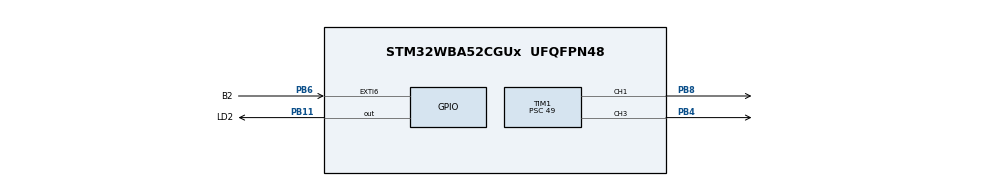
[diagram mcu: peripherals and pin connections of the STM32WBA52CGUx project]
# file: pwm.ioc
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CORTEX_M33_NS.userName=CORTEX_M33
Mcu.Family=STM32WBA
Mcu.Name=STM32WBA52CGUx
Mcu.Package=UFQFPN48
NVIC.EXTI6_IRQn=true\:0\:0\:false\:false\:true\:true\:true\:true
NVIC.PriorityGroup=NVIC_PRIORITYGROUP_4
OSC_IN.GPIO_Label=RCC_OSC_IN
OSC_IN.Mode=HSE-External-Oscillator
OSC_IN.Signal=RCC_OSC_IN
OSC_OUT.GPIO_Label=RCC_OSC_OUT
OSC_OUT.Mode=HSE-External-Oscillator
OSC_OUT.Signal=RCC_OSC_OUT
PA13\ (JTMS/SWDIO).GPIO_Label=DEBUG_JTMS-SWDIO
PA13\ (JTMS/SWDIO).Signal=DEBUG_JTMS-SWDIO
PA14\ (JTCK/SWCLK).GPIO_Label=DEBUG_JTCK-SWCLK
PA14\ (JTCK/SWCLK).Signal=DEBUG_JTCK-SWCLK
PA8.GPIO_Label=USART1_RX
PA8.Signal=USART1_RX
PB11.GPIO_Label=LD2
PB11.GPIO_Speed=GPIO_SPEED_FREQ_HIGH
PB11.Signal=GPIO_Output
PB12.GPIO_Label=USART1_TX
PB12.Signal=USART1_TX
PB4\ (NJTRST).Signal=S_TIM1_CH3
PB6.GPIO_Label=B2
PB6.GPIO_PuPd=GPIO_PULLUP
PB6.Signal=GPXTI6
PB8.Signal=S_TIM1_CH1
PC14-OSC32_IN.GPIO_Label=RCC_OSC32_IN
PC14-OSC32_IN.Signal=RCC_OSC32_IN
PC15-OSC32_OUT.GPIO_Label=RCC_OSC32_OUT
PC15-OSC32_OUT.Signal=RCC_OSC32_OUT
ProjectManager.HeapSize=0x200
ProjectManager.StackSize=0x400
ProjectManager.TargetToolchain=STM32CubeIDE
RCC.ADCFreq_Value=50000000
RCC.AHB5CLKDivider=DIV2
RCC.AHBFreq_Value=50000000
RCC.APB1Freq_Value=50000000
RCC.APB1TimFreq_Value=50000000
RCC.APB2Freq_Value=50000000
RCC.APB2TimFreq_Value=50000000
RCC.CortexFreq_Value=6250000
RCC.HCLKFreq_Value=50000000
RCC.HSE_VALUE=32000000
RCC.HSI_VALUE=16000000
RCC.LSE_VALUE=32768
RCC.PLL1R=3
RCC.PLLFRACN=3072
RCC.PLLN=9
RCC.PWR_Regulator_Voltage_Scale=PWR_REGULATOR_VOLTAGE_SCALE1
RCC.SYSCLKFreq_VALUE=50000000
RCC.SYSCLKSourceVirtual=RCC_SYSCLKSOURCE_PLLCLK
RCC.VCOOutputFreq_Value=150000000
SH.S_TIM1_CH1.0=TIM1_CH1,PWM Generation1 CH1
SH.S_TIM1_CH3.0=TIM1_CH3,PWM Generation3 CH3
TIM1.Channel-PWM\ Generation1\ CH1=TIM_CHANNEL_1
TIM1.Channel-PWM\ Generation3\ CH3=TIM_CHANNEL_3
TIM1.PeriodNoDither=999
TIM1.Prescaler=49
VP_CORTEX_M33_NS_VS_Hclk.Mode=Hclk_Mode
VP_ICACHE_VS_ICACHE.Mode=DirectMappedCache
VP_MEMORYMAP_VS_MEMORYMAP.Mode=CurAppReg
VP_PWR_VS_SECSignals.Mode=Security/Privilege
VP_TIM1_VS_ClockSourceINT.Mode=Internal
board=NUCLEO-WBA52CG

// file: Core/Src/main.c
/* USER CODE BEGIN Header */
/**
  ******************************************************************************
  * @file           : main.c
  * @brief          : Main program body
  ******************************************************************************
  * @attention
  *
  * Copyright (c) 2024 STMicroelectronics.
  * All rights reserved.
  *
  * This software is licensed under terms that can be found in the LICENSE file
  * in the root directory of this software component.
  * If no LICENSE file comes with this software, it is provided AS-IS.
  *
  ******************************************************************************
  */
/* USER CODE END Header */
#include "main.h"

TIM_HandleTypeDef htim1;

void SystemClock_Config(void);
static void MX_GPIO_Init(void);
static void MX_ICACHE_Init(void);
static void MX_TIM1_Init(void);

/* USER CODE BEGIN 0 */
void SetPWMDutyCycle(uint32_t dutyCycle) {
    if (dutyCycle <= 100) {
        uint32_t pulse = (999 * dutyCycle) / 100; // Calculate pulse width
        __HAL_TIM_SET_COMPARE(&htim1, TIM_CHANNEL_1, pulse);
    }
}
    void SetPWMDutyCycle1(uint32_t dutyCycle) {
        if (dutyCycle <= 100) {
            uint32_t pulse = (999 * dutyCycle) / 100; // Calculate pulse width
            __HAL_TIM_SET_COMPARE(&htim1, TIM_CHANNEL_3, pulse);
        }
    }
/* USER CODE END 0 */

int main(void)
{

  /* MCU Configuration--------------------------------------------------------*/

  /* Reset of all peripherals, Initializes the Flash interface and the Systick. */
  HAL_Init();

  /* Configure the system clock */
  SystemClock_Config();

  /* Initialize all configured peripherals */
  MX_GPIO_Init();
  MX_ICACHE_Init();
  MX_TIM1_Init();
  /* USER CODE BEGIN 2 */
  //HAL_TIM_PWM_Start(&htim1,TIM_CHANNEL_1);
  HAL_TIM_PWM_Start(&htim1,TIM_CHANNEL_3);

  /* USER CODE END 2 */

  /* Infinite loop */
  while (1)
  {
	  for (int i = 0; i <= 100; i += 10) {
 	             SetPWMDutyCycle1(i);
	             HAL_Delay(20); // Wait for a second
	         }
	  for (int j = 100; j >= 0; j -= 10) {
		              SetPWMDutyCycle(j);
	 	             HAL_Delay(20); // Wait for a second
	 	         }
	  for (int i = 0; i <= 100; i += 10) {
	 	             SetPWMDutyCycle(i);
	 	             HAL_Delay(20); // Wait for a second
	 	         }
	 	  for (int j = 100; j >= 0; j -= 10) {
	 	 	             SetPWMDutyCycle1(j);
	 	 	             HAL_Delay(20); // Wait for a second
	 	 	         }
  }
}

void SystemClock_Config(void)
{
  RCC_OscInitTypeDef RCC_OscInitStruct = {0};
  RCC_ClkInitTypeDef RCC_ClkInitStruct = {0};

  /** Configure the main internal regulator output voltage
  */
  if (HAL_PWREx_ControlVoltageScaling(PWR_REGULATOR_VOLTAGE_SCALE1) != HAL_OK)
  {
    Error_Handler();
  }

  /** Initializes the CPU, AHB and APB busses clocks
  */
  RCC_OscInitStruct.OscillatorType = RCC_OSCILLATORTYPE_HSI;
  RCC_OscInitStruct.HSIState = RCC_HSI_ON;
  RCC_OscInitStruct.HSICalibrationValue = RCC_HSICALIBRATION_DEFAULT;
  RCC_OscInitStruct.PLL1.PLLState = RCC_PLL_ON;
  RCC_OscInitStruct.PLL1.PLLSource = RCC_PLLSOURCE_HSI;
  RCC_OscInitStruct.PLL1.PLLM = 1;
  RCC_OscInitStruct.PLL1.PLLN = 9;
  RCC_OscInitStruct.PLL1.PLLP = 2;
  RCC_OscInitStruct.PLL1.PLLQ = 2;
  RCC_OscInitStruct.PLL1.PLLR = 3;
  RCC_OscInitStruct.PLL1.PLLFractional = 3072;
  if (HAL_RCC_OscConfig(&RCC_OscInitStruct) != HAL_OK)
  {
    Error_Handler();
  }

  /** Initializes the CPU, AHB and APB busses clocks
  */
  RCC_ClkInitStruct.ClockType = RCC_CLOCKTYPE_HCLK|RCC_CLOCKTYPE_SYSCLK
                              |RCC_CLOCKTYPE_PCLK1|RCC_CLOCKTYPE_PCLK2
                              |RCC_CLOCKTYPE_PCLK7|RCC_CLOCKTYPE_HCLK5;
  RCC_ClkInitStruct.SYSCLKSource = RCC_SYSCLKSOURCE_PLLCLK;
  RCC_ClkInitStruct.AHBCLKDivider = RCC_SYSCLK_DIV1;
  RCC_ClkInitStruct.APB1CLKDivider = RCC_HCLK_DIV1;
  RCC_ClkInitStruct.APB2CLKDivider = RCC_HCLK_DIV1;
  RCC_ClkInitStruct.APB7CLKDivider = RCC_HCLK_DIV1;
  RCC_ClkInitStruct.AHB5_PLL1_CLKDivider = RCC_SYSCLK_PLL1_DIV2;
  RCC_ClkInitStruct.AHB5_HSEHSI_CLKDivider = RCC_SYSCLK_HSEHSI_DIV1;

  if (HAL_RCC_ClockConfig(&RCC_ClkInitStruct, FLASH_LATENCY_1) != HAL_OK)
  {
    Error_Handler();
  }
}

static void MX_ICACHE_Init(void)
{

  /** Enable instruction cache in 1-way (direct mapped cache)
  */
  if (HAL_ICACHE_ConfigAssociativityMode(ICACHE_1WAY) != HAL_OK)
  {
    Error_Handler();
  }
  if (HAL_ICACHE_Enable() != HAL_OK)
  {
    Error_Handler();
  }

}

static void MX_TIM1_Init(void)
{

  TIM_ClockConfigTypeDef sClockSourceConfig = {0};
  TIM_MasterConfigTypeDef sMasterConfig = {0};
  TIM_OC_InitTypeDef sConfigOC = {0};
  TIM_BreakDeadTimeConfigTypeDef sBreakDeadTimeConfig = {0};

  htim1.Instance = TIM1;
  htim1.Init.Prescaler = 49;
  htim1.Init.CounterMode = TIM_COUNTERMODE_UP;
  htim1.Init.Period = 999;
  htim1.Init.ClockDivision = TIM_CLOCKDIVISION_DIV1;
  htim1.Init.RepetitionCounter = 0;
  htim1.Init.AutoReloadPreload = TIM_AUTORELOAD_PRELOAD_DISABLE;
  if (HAL_TIM_Base_Init(&htim1) != HAL_OK)
  {
    Error_Handler();
  }
  sClockSourceConfig.ClockSource = TIM_CLOCKSOURCE_INTERNAL;
  if (HAL_TIM_ConfigClockSource(&htim1, &sClockSourceConfig) != HAL_OK)
  {
    Error_Handler();
  }
  if (HAL_TIM_PWM_Init(&htim1) != HAL_OK)
  {
    Error_Handler();
  }
  sMasterConfig.MasterOutputTrigger = TIM_TRGO_RESET;
  sMasterConfig.MasterOutputTrigger2 = TIM_TRGO2_RESET;
  sMasterConfig.MasterSlaveMode = TIM_MASTERSLAVEMODE_DISABLE;
  if (HAL_TIMEx_MasterConfigSynchronization(&htim1, &sMasterConfig) != HAL_OK)
  {
    Error_Handler();
  }
  sConfigOC.OCMode = TIM_OCMODE_PWM1;
  sConfigOC.Pulse = 0;
  sConfigOC.OCPolarity = TIM_OCPOLARITY_HIGH;
  sConfigOC.OCNPolarity = TIM_OCNPOLARITY_HIGH;
  sConfigOC.OCFastMode = TIM_OCFAST_DISABLE;
  sConfigOC.OCIdleState = TIM_OCIDLESTATE_RESET;
  sConfigOC.OCNIdleState = TIM_OCNIDLESTATE_RESET;
  if (HAL_TIM_PWM_ConfigChannel(&htim1, &sConfigOC, TIM_CHANNEL_1) != HAL_OK)
  {
    Error_Handler();
  }
  if (HAL_TIM_PWM_ConfigChannel(&htim1, &sConfigOC, TIM_CHANNEL_3) != HAL_OK)
  {
    Error_Handler();
  }
  sBreakDeadTimeConfig.OffStateRunMode = TIM_OSSR_DISABLE;
  sBreakDeadTimeConfig.OffStateIDLEMode = TIM_OSSI_DISABLE;
  sBreakDeadTimeConfig.LockLevel = TIM_LOCKLEVEL_OFF;
  sBreakDeadTimeConfig.DeadTime = 0;
  sBreakDeadTimeConfig.BreakState = TIM_BREAK_DISABLE;
  sBreakDeadTimeConfig.BreakPolarity = TIM_BREAKPOLARITY_HIGH;
  sBreakDeadTimeConfig.BreakFilter = 0;
  sBreakDeadTimeConfig.BreakAFMode = TIM_BREAK_AFMODE_INPUT;
  sBreakDeadTimeConfig.Break2State = TIM_BREAK2_DISABLE;
  sBreakDeadTimeConfig.Break2Polarity = TIM_BREAK2POLARITY_HIGH;
  sBreakDeadTimeConfig.Break2Filter = 0;
  sBreakDeadTimeConfig.Break2AFMode = TIM_BREAK_AFMODE_INPUT;
  sBreakDeadTimeConfig.AutomaticOutput = TIM_AUTOMATICOUTPUT_DISABLE;
  if (HAL_TIMEx_ConfigBreakDeadTime(&htim1, &sBreakDeadTimeConfig) != HAL_OK)
  {
    Error_Handler();
  }
  HAL_TIM_MspPostInit(&htim1);

}

static void MX_GPIO_Init(void)
{
  GPIO_InitTypeDef GPIO_InitStruct = {0};

  /* GPIO Ports Clock Enable */
  __HAL_RCC_GPIOB_CLK_ENABLE();
  __HAL_RCC_GPIOA_CLK_ENABLE();
  __HAL_RCC_GPIOC_CLK_ENABLE();

  /*Configure GPIO pin Output Level */
  HAL_GPIO_WritePin(LD2_GPIO_Port, LD2_Pin, GPIO_PIN_SET);

  /*Configure GPIO pin : USART1_TX_Pin */
  GPIO_InitStruct.Pin = USART1_TX_Pin;
  GPIO_InitStruct.Mode = GPIO_MODE_AF_PP;
  GPIO_InitStruct.Pull = GPIO_NOPULL;
  GPIO_InitStruct.Speed = GPIO_SPEED_FREQ_LOW;
  GPIO_InitStruct.Alternate = GPIO_AF7_USART1;
  HAL_GPIO_Init(USART1_TX_GPIO_Port, &GPIO_InitStruct);

  /*Configure GPIO pin : LD2_Pin */
  GPIO_InitStruct.Pin = LD2_Pin;
  GPIO_InitStruct.Mode = GPIO_MODE_OUTPUT_PP;
  GPIO_InitStruct.Pull = GPIO_NOPULL;
  GPIO_InitStruct.Speed = GPIO_SPEED_FREQ_HIGH;
  HAL_GPIO_Init(LD2_GPIO_Port, &GPIO_InitStruct);

  /*Configure GPIO pin : USART1_RX_Pin */
  GPIO_InitStruct.Pin = USART1_RX_Pin;
  GPIO_InitStruct.Mode = GPIO_MODE_AF_PP;
  GPIO_InitStruct.Pull = GPIO_NOPULL;
  GPIO_InitStruct.Speed = GPIO_SPEED_FREQ_LOW;
  GPIO_InitStruct.Alternate = GPIO_AF7_USART1;
  HAL_GPIO_Init(USART1_RX_GPIO_Port, &GPIO_InitStruct);

  /*Configure GPIO pin : B2_Pin */
  GPIO_InitStruct.Pin = B2_Pin;
  GPIO_InitStruct.Mode = GPIO_MODE_IT_RISING;
  GPIO_InitStruct.Pull = GPIO_PULLUP;
  HAL_GPIO_Init(B2_GPIO_Port, &GPIO_InitStruct);

  /* EXTI interrupt init*/
  HAL_NVIC_SetPriority(EXTI6_IRQn, 0, 0);
  HAL_NVIC_EnableIRQ(EXTI6_IRQn);

}

void Error_Handler(void)
{
  __disable_irq();
  while (1)
  {
  }
}
